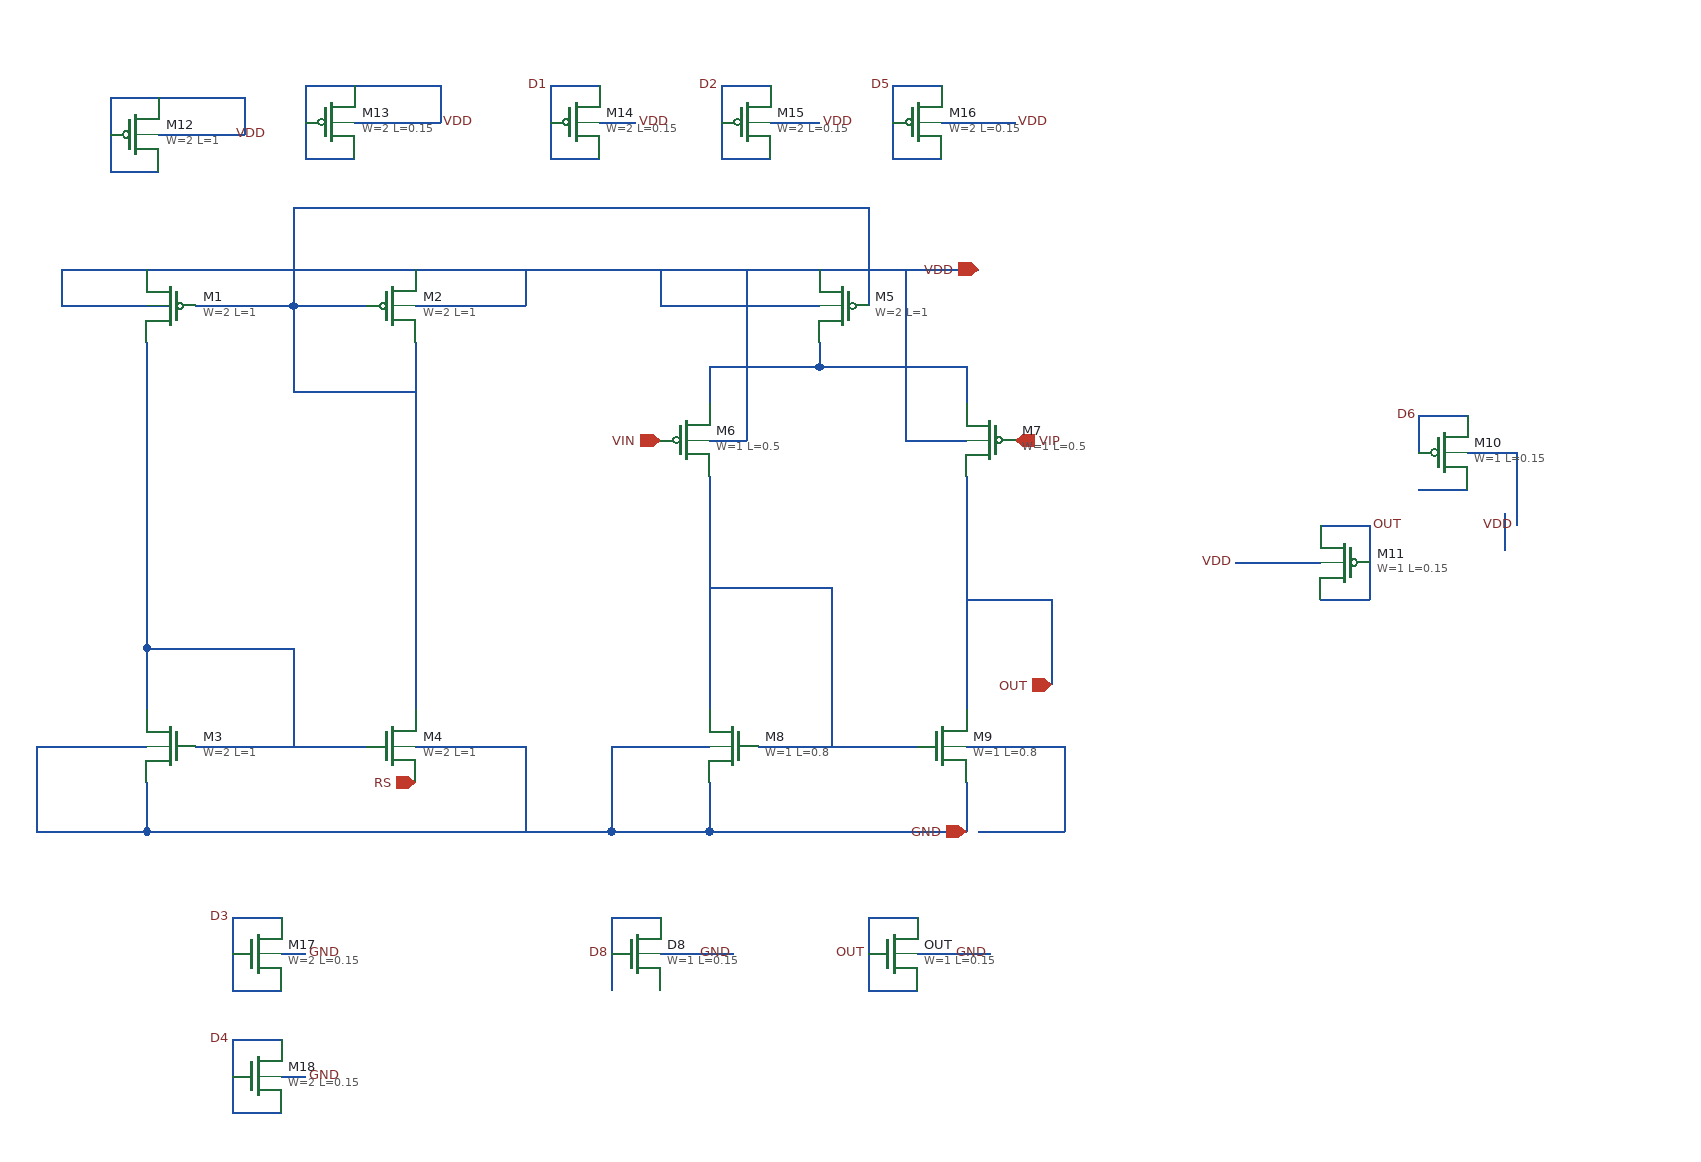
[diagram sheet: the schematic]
v {xschem version=3.4.6RC file_version=1.2
}
G {}
K {}
V {}
S {}
E {}
N -340 -330 -280 -330 {lab=#net1}
N -280 -330 -260 -330 {lab=#net1}
N -260 -330 -200 -330 {lab=#net1}
N -260 -330 -260 -260 {lab=#net1}
N -260 -260 -160 -260 {lab=#net1}
N -160 -300 -160 -260 {lab=#net1}
N -160 -300 -160 -0 {lab=#net1}
N -340 30 -200 30 {lab=#net2}
N -260 -50 -260 30 {lab=#net2}
N -380 -50 -260 -50 {lab=#net2}
N -380 -50 -380 -0 {lab=#net2}
N -380 -300 -380 -50 {lab=#net2}
N -380 60 -380 100 {lab=GND}
N -380 100 -0 100 {lab=GND}
N -0 100 80 100 {lab=GND}
N 80 60 80 100 {lab=GND}
N 290 60 290 100 {lab=GND}
N 80 100 290 100 {lab=GND}
N 120 30 250 30 {lab=#net3}
N 80 -190 80 -0 {lab=#net3}
N 290 -190 290 -0 {lab=OUT}
N 290 -90 360 -90 {lab=OUT}
N 360 -90 360 -20 {lab=OUT}
N 80 -100 180 -100 {lab=#net3}
N 180 -100 180 30 {lab=#net3}
N 80 -280 80 -250 {lab=#net4}
N 80 -280 170 -280 {lab=#net4}
N 170 -280 290 -280 {lab=#net4}
N 290 -280 290 -250 {lab=#net4}
N 170 -300 170 -280 {lab=#net4}
N -380 -360 -160 -360 {lab=VDD}
N -160 -360 170 -360 {lab=VDD}
N 170 -360 300 -360 {lab=VDD}
N -470 30 -380 30 {lab=GND}
N -470 30 -470 100 {lab=GND}
N -470 100 -380 100 {lab=GND}
N -160 30 -70 30 {lab=GND}
N -70 30 -70 100 {lab=GND}
N -390 -330 -360 -330 {lab=VDD}
N 0 30 80 30 {lab=GND}
N 0 30 0 100 {lab=GND}
N 290 30 370 30 {lab=#net5}
N 370 30 370 100 {lab=#net5}
N 300 100 370 100 {lab=#net5}
N 80 -220 110 -220 {lab=VDD}
N 110 -360 110 -220 {lab=VDD}
N 240 -220 290 -220 {lab=VDD}
N 240 -360 240 -220 {lab=VDD}
N 210 -410 210 -330 {lab=#net1}
N -260 -410 210 -410 {lab=#net1}
N -260 -410 -260 -330 {lab=#net1}
N -450 -330 -390 -330 {lab=VDD}
N -450 -360 -450 -330 {lab=VDD}
N -450 -360 -380 -360 {lab=VDD}
N 40 -330 170 -330 {lab=VDD}
N 40 -360 40 -330 {lab=VDD}
N -160 -330 -70 -330 {lab=VDD}
N -70 -360 -70 -330 {lab=VDD}
N 210 200 210 230 {lab=OUT}
N 210 230 250 230 {lab=OUT}
N 210 170 210 200 {lab=OUT}
N 210 170 250 170 {lab=OUT}
N 250 200 310 200 {lab=GND}
N 0 200 0 230 {lab=D8}
N 0 170 0 200 {lab=D8}
N 0 170 40 170 {lab=D8}
N 40 200 100 200 {lab=GND}
N 740 -210 740 -150 {lab=VDD}
N 700 -210 740 -210 {lab=VDD}
N 510 -120 580 -120 {lab=VDD}
N 730 -160 730 -130 {lab=D6}
N 660 -180 700 -180 {lab=D6}
N 620 -150 620 -120 {lab=OUT}
N 580 -150 620 -150 {lab=OUT}
N 580 -90 620 -90 {lab=OUT}
N 620 -120 620 -90 {lab=OUT}
N 660 -240 700 -240 {lab=D6}
N 660 -240 660 -210 {lab=D6}
N -410 -500 -370 -500 {lab=VDD}
N -410 -500 -410 -470 {lab=VDD}
N -410 -470 -410 -440 {lab=VDD}
N -410 -440 -370 -440 {lab=VDD}
N -370 -500 -300 -500 {lab=VDD}
N -300 -500 -300 -470 {lab=VDD}
N -370 -470 -300 -470 {lab=VDD}
N -210 -480 -140 -480 {lab=VDD}
N -140 -510 -140 -480 {lab=VDD}
N -210 -510 -140 -510 {lab=VDD}
N -250 -510 -210 -510 {lab=VDD}
N -250 -510 -250 -480 {lab=VDD}
N -250 -480 -250 -450 {lab=VDD}
N -250 -450 -210 -450 {lab=VDD}
N -50 -510 -10 -510 {lab=D1}
N -50 -510 -50 -480 {lab=D1}
N -50 -480 -50 -450 {lab=D1}
N -50 -450 -10 -450 {lab=D1}
N 90 -450 130 -450 {lab=D2}
N 90 -480 90 -450 {lab=D2}
N 90 -510 90 -480 {lab=D2}
N 90 -510 130 -510 {lab=D2}
N 230 -510 270 -510 {lab=D5}
N 230 -510 230 -480 {lab=D5}
N 230 -480 230 -450 {lab=D5}
N 230 -450 270 -450 {lab=D5}
N -10 -480 20 -480 {lab=VDD}
N 130 -480 170 -480 {lab=VDD}
N 270 -480 330 -480 {lab=VDD}
N -310 170 -270 170 {lab=D3}
N -310 170 -310 230 {lab=D3}
N -310 230 -270 230 {lab=D3}
N -270 200 -250 200 {lab=GND}
N -310 270 -270 270 {lab=D4}
N -270 300 -250 300 {lab=GND}
N -310 270 -310 300 {lab=D4}
N -310 300 -310 330 {lab=D4}
N -310 330 -270 330 {lab=D4}
C {sky130_fd_pr/nfet_01v8.sym} -360 30 0 1 {name=M3
L=1
W=2
nf=1 
mult=2
ad="'int((nf+1)/2) * W/nf * 0.29'" 
pd="'2*int((nf+1)/2) * (W/nf + 0.29)'"
as="'int((nf+2)/2) * W/nf * 0.29'" 
ps="'2*int((nf+2)/2) * (W/nf + 0.29)'"
nrd="'0.29 / W'" nrs="'0.29 / W'"
sa=0 sb=0 sd=0
model=nfet_01v8
spiceprefix=X
}
C {sky130_fd_pr/nfet_01v8.sym} -180 30 0 0 {name=M4
L=1
W=2
nf=1 
mult=2
ad="'int((nf+1)/2) * W/nf * 0.29'" 
pd="'2*int((nf+1)/2) * (W/nf + 0.29)'"
as="'int((nf+2)/2) * W/nf * 0.29'" 
ps="'2*int((nf+2)/2) * (W/nf + 0.29)'"
nrd="'0.29 / W'" nrs="'0.29 / W'"
sa=0 sb=0 sd=0
model=nfet_01v8
spiceprefix=X
}
C {sky130_fd_pr/nfet_01v8.sym} 100 30 0 1 {name=M8
L=0.8
W=1
nf=1 
mult=4
ad="'int((nf+1)/2) * W/nf * 0.29'" 
pd="'2*int((nf+1)/2) * (W/nf + 0.29)'"
as="'int((nf+2)/2) * W/nf * 0.29'" 
ps="'2*int((nf+2)/2) * (W/nf + 0.29)'"
nrd="'0.29 / W'" nrs="'0.29 / W'"
sa=0 sb=0 sd=0
model=nfet_01v8
spiceprefix=X
}
C {sky130_fd_pr/nfet_01v8.sym} 270 30 0 0 {name=M9
L=0.8
W=1
nf=1 
mult=4
ad="'int((nf+1)/2) * W/nf * 0.29'" 
pd="'2*int((nf+1)/2) * (W/nf + 0.29)'"
as="'int((nf+2)/2) * W/nf * 0.29'" 
ps="'2*int((nf+2)/2) * (W/nf + 0.29)'"
nrd="'0.29 / W'" nrs="'0.29 / W'"
sa=0 sb=0 sd=0
model=nfet_01v8
spiceprefix=X
}
C {devices/ipin.sym} 40 -220 0 0 {name=p1 lab=VIN}
C {devices/ipin.sym} 330 -220 0 1 {name=p2 lab=VIP}
C {devices/iopin.sym} 290 100 0 0 {name=p3 lab=GND}
C {devices/iopin.sym} -160 60 0 0 {name=p4 lab=RS}
C {devices/iopin.sym} 360 -20 0 0 {name=p5 lab=OUT}
C {devices/iopin.sym} 300 -360 0 0 {name=p6 lab=VDD}
C {sky130_fd_pr/pfet_01v8.sym} 60 -220 0 0 {name=M6
L=0.5
W=1
nf=1
mult=4
ad="'int((nf+1)/2) * W/nf * 0.29'" 
pd="'2*int((nf+1)/2) * (W/nf + 0.29)'"
as="'int((nf+2)/2) * W/nf * 0.29'" 
ps="'2*int((nf+2)/2) * (W/nf + 0.29)'"
nrd="'0.29 / W'" nrs="'0.29 / W'"
sa=0 sb=0 sd=0
model=pfet_01v8
spiceprefix=X
}
C {sky130_fd_pr/pfet_01v8.sym} -360 -330 0 1 {name=M1
L=1
W=2
nf=1
mult=2
ad="'int((nf+1)/2) * W/nf * 0.29'" 
pd="'2*int((nf+1)/2) * (W/nf + 0.29)'"
as="'int((nf+2)/2) * W/nf * 0.29'" 
ps="'2*int((nf+2)/2) * (W/nf + 0.29)'"
nrd="'0.29 / W'" nrs="'0.29 / W'"
sa=0 sb=0 sd=0
model=pfet_01v8
spiceprefix=X
}
C {sky130_fd_pr/pfet_01v8.sym} 310 -220 0 1 {name=M7
L=0.5
W=1
nf=1
mult=4
ad="'int((nf+1)/2) * W/nf * 0.29'" 
pd="'2*int((nf+1)/2) * (W/nf + 0.29)'"
as="'int((nf+2)/2) * W/nf * 0.29'" 
ps="'2*int((nf+2)/2) * (W/nf + 0.29)'"
nrd="'0.29 / W'" nrs="'0.29 / W'"
sa=0 sb=0 sd=0
model=pfet_01v8
spiceprefix=X
}
C {sky130_fd_pr/pfet_01v8.sym} -180 -330 0 0 {name=M2
L=1
W=2
nf=1
mult=2
ad="'int((nf+1)/2) * W/nf * 0.29'" 
pd="'2*int((nf+1)/2) * (W/nf + 0.29)'"
as="'int((nf+2)/2) * W/nf * 0.29'" 
ps="'2*int((nf+2)/2) * (W/nf + 0.29)'"
nrd="'0.29 / W'" nrs="'0.29 / W'"
sa=0 sb=0 sd=0
model=pfet_01v8
spiceprefix=X
}
C {sky130_fd_pr/pfet_01v8.sym} 190 -330 0 1 {name=M5
L=1
W=2
nf=1
mult=2
ad="'int((nf+1)/2) * W/nf * 0.29'" 
pd="'2*int((nf+1)/2) * (W/nf + 0.29)'"
as="'int((nf+2)/2) * W/nf * 0.29'" 
ps="'2*int((nf+2)/2) * (W/nf + 0.29)'"
nrd="'0.29 / W'" nrs="'0.29 / W'"
sa=0 sb=0 sd=0
model=pfet_01v8
spiceprefix=X
}
C {sky130_fd_pr/nfet_01v8.sym} 230 200 0 0 {name=OUT
L=0.15
W=1
nf=1 
mult=2
ad="'int((nf+1)/2) * W/nf * 0.29'" 
pd="'2*int((nf+1)/2) * (W/nf + 0.29)'"
as="'int((nf+2)/2) * W/nf * 0.29'" 
ps="'2*int((nf+2)/2) * (W/nf + 0.29)'"
nrd="'0.29 / W'" nrs="'0.29 / W'"
sa=0 sb=0 sd=0
model=nfet_01v8
spiceprefix=X
}
C {sky130_fd_pr/nfet_01v8.sym} 20 200 0 0 {name=D8
L=0.15
W=1
nf=1 
mult=2
ad="'int((nf+1)/2) * W/nf * 0.29'" 
pd="'2*int((nf+1)/2) * (W/nf + 0.29)'"
as="'int((nf+2)/2) * W/nf * 0.29'" 
ps="'2*int((nf+2)/2) * (W/nf + 0.29)'"
nrd="'0.29 / W'" nrs="'0.29 / W'"
sa=0 sb=0 sd=0
model=nfet_01v8
spiceprefix=X
}
C {devices/lab_pin.sym} 0 200 0 0 {name=p7 sig_type=std_logic lab=D8}
C {devices/lab_pin.sym} 210 200 0 0 {name=p8 sig_type=std_logic lab=OUT}
C {devices/lab_pin.sym} 310 200 0 0 {name=p9 sig_type=std_logic lab=GND}
C {devices/lab_pin.sym} 70 200 0 1 {name=p10 sig_type=std_logic lab=GND}
C {sky130_fd_pr/pfet_01v8.sym} 680 -210 0 0 {name=M10
L=0.15
W=1
body=VDD
nf=1
mult=4
ad="'int((nf+1)/2) * W/nf * 0.29'" 
pd="'2*int((nf+1)/2) * (W/nf + 0.29)'"
as="'int((nf+2)/2) * W/nf * 0.29'" 
ps="'2*int((nf+2)/2) * (W/nf + 0.29)'"
nrd="'0.29 / W'" nrs="'0.29 / W'"
sa=0 sb=0 sd=0
model=pfet_01v8
spiceprefix=X
}
C {sky130_fd_pr/pfet_01v8.sym} 600 -120 0 1 {name=M11
L=0.15
W=1
body=VDD
nf=1
mult=4
ad="'int((nf+1)/2) * W/nf * 0.29'" 
pd="'2*int((nf+1)/2) * (W/nf + 0.29)'"
as="'int((nf+2)/2) * W/nf * 0.29'" 
ps="'2*int((nf+2)/2) * (W/nf + 0.29)'"
nrd="'0.29 / W'" nrs="'0.29 / W'"
sa=0 sb=0 sd=0
model=pfet_01v8
spiceprefix=X
}
C {devices/lab_pin.sym} 660 -240 0 0 {name=p11 sig_type=std_logic lab=D6}
C {devices/lab_pin.sym} 620 -150 0 1 {name=p12 sig_type=std_logic lab=OUT}
C {devices/lab_pin.sym} 510 -120 2 1 {name=p13 sig_type=std_logic lab=VDD}
C {devices/lab_pin.sym} 740 -150 2 1 {name=p14 sig_type=std_logic lab=VDD}
C {sky130_fd_pr/pfet_01v8.sym} -390 -470 0 0 {name=M12
L=1
W=2
nf=1
mult=2
ad="'int((nf+1)/2) * W/nf * 0.29'" 
pd="'2*int((nf+1)/2) * (W/nf + 0.29)'"
as="'int((nf+2)/2) * W/nf * 0.29'" 
ps="'2*int((nf+2)/2) * (W/nf + 0.29)'"
nrd="'0.29 / W'" nrs="'0.29 / W'"
sa=0 sb=0 sd=0
model=pfet_01v8
spiceprefix=X
}
C {sky130_fd_pr/pfet_01v8.sym} -230 -480 0 0 {name=M13
L=0.15
W=2
nf=1
mult=2
ad="'int((nf+1)/2) * W/nf * 0.29'" 
pd="'2*int((nf+1)/2) * (W/nf + 0.29)'"
as="'int((nf+2)/2) * W/nf * 0.29'" 
ps="'2*int((nf+2)/2) * (W/nf + 0.29)'"
nrd="'0.29 / W'" nrs="'0.29 / W'"
sa=0 sb=0 sd=0
model=pfet_01v8
spiceprefix=X
}
C {sky130_fd_pr/pfet_01v8.sym} -30 -480 0 0 {name=M14
L=0.15
W=2
nf=1
mult=2
ad="'int((nf+1)/2) * W/nf * 0.29'" 
pd="'2*int((nf+1)/2) * (W/nf + 0.29)'"
as="'int((nf+2)/2) * W/nf * 0.29'" 
ps="'2*int((nf+2)/2) * (W/nf + 0.29)'"
nrd="'0.29 / W'" nrs="'0.29 / W'"
sa=0 sb=0 sd=0
model=pfet_01v8
spiceprefix=X
}
C {sky130_fd_pr/pfet_01v8.sym} 110 -480 0 0 {name=M15
L=0.15
W=2
nf=1
mult=2
ad="'int((nf+1)/2) * W/nf * 0.29'" 
pd="'2*int((nf+1)/2) * (W/nf + 0.29)'"
as="'int((nf+2)/2) * W/nf * 0.29'" 
ps="'2*int((nf+2)/2) * (W/nf + 0.29)'"
nrd="'0.29 / W'" nrs="'0.29 / W'"
sa=0 sb=0 sd=0
model=pfet_01v8
spiceprefix=X
}
C {sky130_fd_pr/pfet_01v8.sym} 250 -480 0 0 {name=M16
L=0.15
W=2
nf=1
mult=2
ad="'int((nf+1)/2) * W/nf * 0.29'" 
pd="'2*int((nf+1)/2) * (W/nf + 0.29)'"
as="'int((nf+2)/2) * W/nf * 0.29'" 
ps="'2*int((nf+2)/2) * (W/nf + 0.29)'"
nrd="'0.29 / W'" nrs="'0.29 / W'"
sa=0 sb=0 sd=0
model=pfet_01v8
spiceprefix=X
}
C {devices/lab_pin.sym} 330 -480 2 0 {name=p15 sig_type=std_logic lab=VDD}
C {devices/lab_pin.sym} 170 -480 2 0 {name=p16 sig_type=std_logic lab=VDD}
C {devices/lab_pin.sym} 20 -480 2 0 {name=p17 sig_type=std_logic lab=VDD}
C {devices/lab_pin.sym} -140 -480 2 0 {name=p18 sig_type=std_logic lab=VDD}
C {devices/lab_pin.sym} -310 -470 2 0 {name=p19 sig_type=std_logic lab=VDD}
C {devices/lab_pin.sym} -50 -510 0 0 {name=p20 sig_type=std_logic lab=D1}
C {devices/lab_pin.sym} 90 -510 0 0 {name=p21 sig_type=std_logic lab=D2}
C {devices/lab_pin.sym} 230 -510 0 0 {name=p22 sig_type=std_logic lab=D5}
C {sky130_fd_pr/nfet_01v8.sym} -290 200 0 0 {name=M17
L=0.15
W=2
nf=1 
mult=2
ad="'int((nf+1)/2) * W/nf * 0.29'" 
pd="'2*int((nf+1)/2) * (W/nf + 0.29)'"
as="'int((nf+2)/2) * W/nf * 0.29'" 
ps="'2*int((nf+2)/2) * (W/nf + 0.29)'"
nrd="'0.29 / W'" nrs="'0.29 / W'"
sa=0 sb=0 sd=0
model=nfet_01v8
spiceprefix=X
}
C {devices/lab_pin.sym} -310 170 0 0 {name=p23 sig_type=std_logic lab=D3}
C {sky130_fd_pr/nfet_01v8.sym} -290 300 0 0 {name=M18
L=0.15
W=2
nf=1 
mult=2
ad="'int((nf+1)/2) * W/nf * 0.29'" 
pd="'2*int((nf+1)/2) * (W/nf + 0.29)'"
as="'int((nf+2)/2) * W/nf * 0.29'" 
ps="'2*int((nf+2)/2) * (W/nf + 0.29)'"
nrd="'0.29 / W'" nrs="'0.29 / W'"
sa=0 sb=0 sd=0
model=nfet_01v8
spiceprefix=X
}
C {devices/lab_pin.sym} -310 270 0 0 {name=p24 sig_type=std_logic lab=D4}
C {devices/lab_pin.sym} -250 200 2 0 {name=p25 sig_type=std_logic lab=GND}
C {devices/lab_pin.sym} -250 300 2 0 {name=p26 sig_type=std_logic lab=GND}
